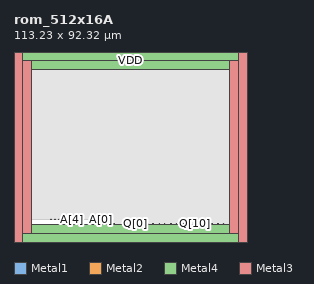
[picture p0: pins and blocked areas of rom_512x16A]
MACRO rom_512x16A
  CLASS RING ;
  FOREIGN rom_512x16A 0 0 ;
  ORIGIN 0 0 ;
  SIZE 113.23 BY 92.32 ;
  SYMMETRY X Y R90 ;
  PIN A[0]
    DIRECTION INPUT ;
    USE SIGNAL ;
    AntennaGateArea  0.039 ;
    PORT
      LAYER Metal1 ;
        RECT 42.27 10.76 42.6 11.09 ;
      LAYER Metal2 ;
        RECT 42.27 10.76 42.6 11.09 ;
      LAYER Metal4 ;
        RECT 42.27 10.76 42.6 11.09 ;
      LAYER Metal3 ;
        RECT 42.27 10.76 42.6 11.09 ;
      END
    END A[0]
  PIN A[1]
    DIRECTION INPUT ;
    USE SIGNAL ;
    AntennaGateArea  0.039 ;
    PORT
      LAYER Metal1 ;
        RECT 40.22 10.76 40.55 11.09 ;
      LAYER Metal2 ;
        RECT 40.22 10.76 40.55 11.09 ;
      LAYER Metal4 ;
        RECT 40.22 10.76 40.55 11.09 ;
      LAYER Metal3 ;
        RECT 40.22 10.76 40.55 11.09 ;
      END
    END A[1]
  PIN A[2]
    DIRECTION INPUT ;
    AntennaGateArea  0.039 ;
    USE SIGNAL ;
    PORT
      LAYER Metal1 ;
        RECT 38.17 10.76 38.5 11.09 ;
      LAYER Metal2 ;
        RECT 38.17 10.76 38.5 11.09 ;
      LAYER Metal4 ;
        RECT 38.17 10.76 38.5 11.09 ;
      LAYER Metal3 ;
        RECT 38.17 10.76 38.5 11.09 ;
      END
    END A[2]
  PIN A[3]
    DIRECTION INPUT ;
    USE SIGNAL ;
    AntennaGateArea  0.039 ;
    PORT
      LAYER Metal1 ;
        RECT 29.97 10.76 30.3 11.09 ;
      LAYER Metal2 ;
        RECT 29.97 10.76 30.3 11.09 ;
      LAYER Metal4 ;
        RECT 29.97 10.76 30.3 11.09 ;
      LAYER Metal3 ;
        RECT 29.97 10.76 30.3 11.09 ;
      END
    END A[3]
  PIN A[4]
    DIRECTION INPUT ;
    USE SIGNAL ;
    AntennaGateArea  0.039 ;
    PORT
      LAYER Metal1 ;
        RECT 27.92 10.76 28. 11.09 ;
      LAYER Metal2 ;
        RECT 27.92 10.76 28. 11.09 ;
      LAYER Metal4 ;
        RECT 27.92 10.76 28. 11.09 ;
      LAYER Metal3 ;
        RECT 27.92 10.76 28. 11.09 ;
      END
    END A[4]
  PIN A[5]
    DIRECTION INPUT ;
    USE SIGNAL ;
    AntennaGateArea  0.039 ;
    PORT
      LAYER Metal1 ;
        RECT 25.87 10.76 26.2 11.09 ;
      LAYER Metal2 ;
        RECT 25.87 10.76 26.2 11.09 ;
      LAYER Metal4 ;
        RECT 25.87 10.76 26.2 11.09 ;
      LAYER Metal3 ;
        RECT 25.87 10.76 26.2 11.09 ;
      END
    END A[5]
  PIN A[6]
    DIRECTION INPUT ;
    USE SIGNAL ;
    AntennaGateArea  0.039 ;
    PORT
      LAYER Metal1 ;
        RECT 21.77 10.76 22.1 11.09 ;
      LAYER Metal2 ;
        RECT 21.77 10.76 22.1 11.09 ;
      LAYER Metal4 ;
        RECT 21.77 10.76 22.1 11.09 ;
      LAYER Metal3 ;
        RECT 21.77 10.76 22.1 11.09 ;
      END
    END A[6]
  PIN A[7]
    DIRECTION INPUT ;
    USE SIGNAL ;
    AntennaGateArea  0.039 ;
    PORT
      LAYER Metal1 ;
        RECT 19.72 10.76 20.05 11.09 ;
      LAYER Metal2 ;
        RECT 19.72 10.76 20.05 11.09 ;
      LAYER Metal4 ;
        RECT 19.72 10.76 20.05 11.09 ;
      LAYER Metal3 ;
        RECT 19.72 10.76 20.05 11.09 ;
      END
    END A[7]
  PIN A[8]
    DIRECTION INPUT ;
    USE SIGNAL ;
    AntennaGateArea  0.039 ;
    PORT
      LAYER Metal1 ;
        RECT 17.67 10.76 18 11.09 ;
      LAYER Metal2 ;
        RECT 17.67 10.76 18 11.09 ;
      LAYER Metal4 ;
        RECT 17.67 10.76 18 11.09 ;
      LAYER Metal3 ;
        RECT 17.67 10.76 18 11.09 ;
      END
    END A[8]
  PIN CEN
    DIRECTION INPUT ;
    USE SIGNAL ;
    AntennaGateArea  0.039 ;
    PORT
      LAYER Metal1 ;
        RECT 46.955 8.6 47.285 8.93 ;
      LAYER Metal2 ;
        RECT 46.955 8.6 47.285 8.93 ;
      LAYER Metal4 ;
        RECT 46.955 8.6 47.285 8.93 ;
      LAYER Metal3 ;
        RECT 46.955 8.6 47.285 8.93 ;
      END
    END CEN
  PIN CLK
    DIRECTION INPUT ;
    USE CLOCK ;
    AntennaGateArea  0.039 ;
    PORT
      LAYER Metal1 ;
        RECT 48.53 8.6 48.86 8.93 ;
      LAYER Metal2 ;
        RECT 48.53 8.6 48.86 8.93 ;
      LAYER Metal4 ;
        RECT 48.53 8.6 48.86 8.93 ;
      LAYER Metal3 ;
        RECT 48.53 8.6 48.86 8.93 ;
      END
    END CLK
  PIN Q[0]
    DIRECTION OUTPUT ;
    USE SIGNAL ;
    ANTENNADIFFAREA 1.7285  LAYER Metal1 ;
    PORT
      LAYER Metal1 ;
        RECT 59.02 8.6 59.35 8.93 ;
      LAYER Metal2 ;
        RECT 59.02 8.6 59.35 8.93 ;
      LAYER Metal4 ;
        RECT 59.02 8.6 59.35 8.93 ;
      LAYER Metal3 ;
        RECT 59.02 8.6 59.35 8.93 ;
      END
    END Q[0]
  PIN Q[10]
    DIRECTION OUTPUT ;
    USE SIGNAL ;
    ANTENNADIFFAREA 1.7285  LAYER Metal1 ;
    PORT
      LAYER Metal1 ;
        RECT 87.62 8.6 87.95 8.93 ;
      LAYER Metal2 ;
        RECT 87.62 8.6 87.95 8.93 ;
      LAYER Metal4 ;
        RECT 87.62 8.6 87.95 8.93 ;
      LAYER Metal3 ;
        RECT 87.62 8.6 87.95 8.93 ;
      END
    END Q[10]
  PIN Q[11]
    DIRECTION OUTPUT ;
    USE SIGNAL ;
    ANTENNADIFFAREA 1.7285  LAYER Metal1 ;
    PORT
      LAYER Metal1 ;
        RECT 90.18 8.6 90.51 8.93 ;
      LAYER Metal2 ;
        RECT 90.18 8.6 90.51 8.93 ;
      LAYER Metal4 ;
        RECT 90.18 8.6 90.51 8.93 ;
      LAYER Metal3 ;
        RECT 90.18 8.6 90.51 8.93 ;
      END
    END Q[11]
  PIN Q[12]
    DIRECTION OUTPUT ;
    USE SIGNAL ;
    ANTENNADIFFAREA 1.7285  LAYER Metal1 ;
    PORT
      LAYER Metal1 ;
        RECT 93.34 8.6 93.67 8.93 ;
      LAYER Metal2 ;
        RECT 93.34 8.6 93.67 8.93 ;
      LAYER Metal4 ;
        RECT 93.34 8.6 93.67 8.93 ;
      LAYER Metal3 ;
        RECT 93.34 8.6 93.67 8.93 ;
      END
    END Q[12]
  PIN Q[13]
    DIRECTION OUTPUT ;
    USE SIGNAL ;
    ANTENNADIFFAREA 1.7285  LAYER Metal1 ;
    PORT
      LAYER Metal1 ;
        RECT 95.90 8.6 96.23 8.93 ;
      LAYER Metal2 ;
        RECT 95.90 8.6 96.23 8.93 ;
      LAYER Metal4 ;
        RECT 95.90 8.6 96.23 8.93 ;
      LAYER Metal3 ;
        RECT 95.90 8.6 96.23 8.93 ;
      END
    END Q[13]
  PIN Q[14]
    DIRECTION OUTPUT ;
    USE SIGNAL ;
    ANTENNADIFFAREA 1.7285  LAYER Metal1 ;
    PORT
      LAYER Metal1 ;
        RECT 99.06 8.6 99.39 8.93 ;
      LAYER Metal2 ;
        RECT 99.06 8.6 99.39 8.93 ;
      LAYER Metal4 ;
        RECT 99.06 8.6 99.39 8.93 ;
      LAYER Metal3 ;
        RECT 99.06 8.6 99.39 8.93 ;
      END
    END Q[14]
  PIN Q[15]
    DIRECTION OUTPUT ;
    USE SIGNAL ;
    ANTENNADIFFAREA 1.7285  LAYER Metal1 ;
    PORT
      LAYER Metal1 ;
        RECT 101.62 8.6 101.95 8.93 ;
      LAYER Metal2 ;
        RECT 101.62 8.6 101.95 8.93 ;
      LAYER Metal4 ;
        RECT 101.62 8.6 101.95 8.93 ;
      LAYER Metal3 ;
        RECT 101.62 8.6 101.95 8.93 ;
      END
    END Q[15]
  PIN Q[1]
    DIRECTION OUTPUT ;
    USE SIGNAL ;
    ANTENNADIFFAREA 1.7285  LAYER Metal1 ;
    PORT
      LAYER Metal1 ;
        RECT 61.58 8.6 61.91 8.93 ;
      LAYER Metal2 ;
        RECT 61.58 8.6 61.91 8.93 ;
      LAYER Metal4 ;
        RECT 61.58 8.6 61.91 8.93 ;
      LAYER Metal3 ;
        RECT 61.58 8.6 61.91 8.93 ;
      END
    END Q[1]
  PIN Q[2]
    DIRECTION OUTPUT ;
    USE SIGNAL ;
    ANTENNADIFFAREA 1.7285  LAYER Metal1 ;
    PORT
      LAYER Metal1 ;
        RECT 64.74 8.6 65.07 8.93 ;
      LAYER Metal2 ;
        RECT 64.74 8.6 65.07 8.93 ;
      LAYER Metal4 ;
        RECT 64.74 8.6 65.07 8.93 ;
      LAYER Metal3 ;
        RECT 64.74 8.6 65.07 8.93 ;
      END
    END Q[2]
  PIN Q[3]
    DIRECTION OUTPUT ;
    USE SIGNAL ;
    ANTENNADIFFAREA 1.7285  LAYER Metal1 ;
    PORT
      LAYER Metal1 ;
        RECT 67.30 8.6 67.63 8.93 ;
      LAYER Metal2 ;
        RECT 67.30 8.6 67.63 8.93 ;
      LAYER Metal4 ;
        RECT 67.30 8.6 67.63 8.93 ;
      LAYER Metal3 ;
        RECT 67.30 8.6 67.63 8.93 ;
      END
    END Q[3]
  PIN Q[4]
    DIRECTION OUTPUT ;
    USE SIGNAL ;
    ANTENNADIFFAREA 1.7285  LAYER Metal1 ;
    PORT
      LAYER Metal1 ;
        RECT 70.46 8.6 70.79 8.93 ;
      LAYER Metal2 ;
        RECT 70.46 8.6 70.79 8.93 ;
      LAYER Metal4 ;
        RECT 70.46 8.6 70.79 8.93 ;
      LAYER Metal3 ;
        RECT 70.46 8.6 70.79 8.93 ;
      END
    END Q[4]
  PIN Q[5]
    DIRECTION OUTPUT ;
    USE SIGNAL ;
    ANTENNADIFFAREA 1.7285  LAYER Metal1 ;
    PORT
      LAYER Metal1 ;
        RECT 73.02 8.6 73.35 8.93 ;
      LAYER Metal2 ;
        RECT 73.02 8.6 73.35 8.93 ;
      LAYER Metal4 ;
        RECT 73.02 8.6 73.35 8.93 ;
      LAYER Metal3 ;
        RECT 73.02 8.6 73.35 8.93 ;
      END
    END Q[5]
  PIN Q[6]
    DIRECTION OUTPUT ;
    USE SIGNAL ;
    ANTENNADIFFAREA 1.7285  LAYER Metal1 ;
    PORT
      LAYER Metal1 ;
        RECT 76.18 8.6 76.51 8.93 ;
      LAYER Metal2 ;
        RECT 76.18 8.6 76.51 8.93 ;
      LAYER Metal4 ;
        RECT 76.18 8.6 76.51 8.93 ;
      LAYER Metal3 ;
        RECT 76.18 8.6 76.51 8.93 ;
      END
    END Q[6]
  PIN Q[7]
    DIRECTION OUTPUT ;
    USE SIGNAL ;
    ANTENNADIFFAREA 1.7285  LAYER Metal1 ;
    PORT
      LAYER Metal1 ;
        RECT 78.74 8.6 79.07 8.93 ;
      LAYER Metal2 ;
        RECT 78.74 8.6 79.07 8.93 ;
      LAYER Metal4 ;
        RECT 78.74 8.6 79.07 8.93 ;
      LAYER Metal3 ;
        RECT 78.74 8.6 79.07 8.93 ;
      END
    END Q[7]
  PIN Q[8]
    DIRECTION OUTPUT ;
    USE SIGNAL ;
    ANTENNADIFFAREA 1.7285  LAYER Metal1 ;
    PORT
      LAYER Metal1 ;
        RECT 81.90 8.6 82.23 8.93 ;
      LAYER Metal2 ;
        RECT 81.90 8.6 82.23 8.93 ;
      LAYER Metal4 ;
        RECT 81.90 8.6 82.23 8.93 ;
      LAYER Metal3 ;
        RECT 81.90 8.6 82.23 8.93 ;
      END
    END Q[8]
  PIN Q[9]
    DIRECTION OUTPUT ;
    USE SIGNAL ;
    ANTENNADIFFAREA 1.7285  LAYER Metal1 ;
    PORT
      LAYER Metal1 ;
        RECT 84.46 8.6 84.79 8.93 ;
      LAYER Metal2 ;
        RECT 84.46 8.6 84.79 8.93 ;
      LAYER Metal4 ;
        RECT 84.46 8.6 84.79 8.93 ;
      LAYER Metal3 ;
        RECT 84.46 8.6 84.79 8.93 ;
      END
    END Q[9]
  PIN VDD
    DIRECTION INOUT ;
    USE POWER ;
    SHAPE RING ;
    PORT
      LAYER Metal4 ;
        RECT 113.23 88.32 0 92.32 ;
      LAYER Metal4 ;
        RECT 0 0 113.23 4 ;
      LAYER Metal3 ;
        RECT 109.23 0 113.23 92.32 ;
      LAYER Metal3 ;
        RECT 0 92.32 4 0 ;
      END
    END VDD
  PIN VSS
    DIRECTION INOUT ;
    USE GROUND ;
    SHAPE RING ;
    PORT
      LAYER Metal4 ;
        RECT 108.93 84.02 4.3 88.02 ;
      LAYER Metal4 ;
        RECT 4.3 4.3 108.93 8.3 ;
      LAYER Metal3 ;
        RECT 104.93 4.3 108.93 88.02 ;
      LAYER Metal3 ;
        RECT 4.3 88.02 8.3 4.3 ;
      END
    END VSS
  OBS
    LAYER OVERLAP ;
POLYGON 8.6 10.76 45.995 10.76 45.995 8.6 104.63 8.6 104.63 83.72 
8.6 83.72 ; 
    LAYER Via1 ;
POLYGON 8.6 10.76 45.995 10.76 45.995 8.6 104.63 8.6 104.63 83.72 
8.6 83.72 ; 
    LAYER Via2 ;
POLYGON 8.6 10.76 45.995 10.76 45.995 8.6 104.63 8.6 104.63 83.72 
8.6 83.72 ; 
    LAYER Via3 ;
POLYGON 8.6 10.76 45.995 10.76 45.995 8.6 104.63 8.6 104.63 83.72 
8.6 83.72 ; 
    LAYER Via4 ;
POLYGON 8.6 10.76 45.995 10.76 45.995 8.6 104.63 8.6 104.63 83.72 
8.6 83.72 ; 
    LAYER Metal1 ;
POLYGON 8.6 83.72 8.6 10.76 17.58 10.76 17.58 11.18 18.09 11.18 
18.09 10.76 19.63 10.76 19.63 11.18 20.14 11.18 20.14 10.76 21.68 10.76 
21.68 11.18 22.19 11.18 22.19 10.76 25.78 10.76 25.78 11.18 26.29 11.18 
26.29 10.76 27.83 10.76 27.83 11.18 28.34 11.18 28.34 10.76 29.88 10.76 
29.88 11.18 30.39 11.18 30.39 10.76 38.08 10.76 38.08 11.18 38.59 11.18 
38.59 10.76 40.13 10.76 40.13 11.18 40.64 11.18 40.64 10.76 42.18 10.76 
42.18 11.18 42.69 11.18 42.69 10.76 45.995 10.76 45.995 8.6 46.865 8.6 
46.865 9.02 47.3 9.02 47.3 8.6 48.44 8.6 48.44 9.02 
48.95 9.02 48.95 8.6 58.93 8.6 58.93 9.02 59.44 9.02 
59.44 8.6 61.49 8.6 61.49 9.02 62.00 9.02 62.00 8.6 
64.65 8.6 64.65 9.02 65.16 9.02 65.16 8.6 67.21 8.6 
67.21 9.02 67.72 9.02 67.72 8.6 70.37 8.6 70.37 9.02 
70.88 9.02 70.88 8.6 72.93 8.6 72.93 9.02 73.44 9.02 
73.44 8.6 76.09 8.6 76.09 9.02 76.60 9.02 76.60 8.6 
78.65 8.6 78.65 9.02 79.16 9.02 79.16 8.6 81.81 8.6 
81.81 9.02 82.32 9.02 82.32 8.6 84.37 8.6 84.37 9.02 
84.88 9.02 84.88 8.6 87.53 8.6 87.53 9.02 88.04 9.02 
88.04 8.6 90.09 8.6 90.09 9.02 90.60 9.02 90.60 8.6 
93.25 8.6 93.25 9.02 93.76 9.02 93.76 8.6 95.81 8.6 
95.81 9.02 96.32 9.02 96.32 8.6 98.97 8.6 98.97 9.02 
99.48 9.02 99.48 8.6 101.53 8.6 101.53 9.02 102.04 9.02 
102.04 8.6 104.63 8.6 104.63 83.72 ; 
    LAYER Metal2 ;
POLYGON 8.6 83.72 8.6 10.76 17.565 10.76 17.565 11.195 18.105 11.195 
18.105 10.76 19.615 10.76 19.615 11.195 20.155 11.195 20.155 10.76 21.665 10.76 
21.665 11.195 22.205 11.195 22.205 10.76 25.765 10.76 25.765 11.195 26.305 11.195 
26.305 10.76 27.815 10.76 27.815 11.195 28.355 11.195 28.355 10.76 29.865 10.76 
29.865 11.195 30.405 11.195 30.405 10.76 38.065 10.76 38.065 11.195 38.605 11.195 
38.605 10.76 40.115 10.76 40.115 11.195 40.655 11.195 40.655 10.76 42.165 10.76 
42.165 11.195 42.705 11.195 42.705 10.76 45.995 10.76 45.995 8.6 46.85 8.6 
46.85 9.035 47.39 9.035 47.39 8.6 48.42 8.6 48.42 9.035 48.96 9.035 
48.96 8.6 58.92 8.6 58.92 9.035 59.46 9.035 59.46 8.6 
61.48 8.6 61.48 9.035 62.02 9.035 62.02 8.6 64.64 8.6 
64.64 9.035 65.18 9.035 65.18 8.6 67.20 8.6 67.20 9.035 
67.74 9.035 67.74 8.6 70.36 8.6 70.36 9.035 70.90 9.035 
70.90 8.6 72.92 8.6 72.92 9.035 73.46 9.035 73.46 8.6 
76.08 8.6 76.08 9.035 76.62 9.035 76.62 8.6 78.64 8.6 
78.64 9.035 79.18 9.035 79.18 8.6 81.80 8.6 81.80 9.035 
82.34 9.035 82.34 8.6 84.36 8.6 84.36 9.035 84.90 9.035 
84.90 8.6 87.52 8.6 87.52 9.035 88.06 9.035 88.06 8.6 
90.08 8.6 90.08 9.035 90.62 9.035 90.62 8.6 93.24 8.6 
93.24 9.035 93.78 9.035 93.78 8.6 95.80 8.6 95.80 9.035 
96.34 9.035 96.34 8.6 98.96 8.6 98.96 9.035 99.50 9.035 
99.50 8.6 101.52 8.6 101.52 9.035 102.06 9.035 102.06 8.6 
104.63 8.6 104.63 83.72 ; 
    LAYER Metal4 ;
POLYGON 8.6 83.72 8.6 10.76 17.565 10.76 17.565 11.195 18.105 11.195 
18.105 10.76 19.615 10.76 19.615 11.195 20.155 11.195 20.155 10.76 21.665 10.76 
21.665 11.195 22.205 11.195 22.205 10.76 25.765 10.76 25.765 11.195 26.305 11.195 
26.305 10.76 27.815 10.76 27.815 11.195 28.355 11.195 28.355 10.76 29.865 10.76 
29.865 11.195 30.405 11.195 30.405 10.76 38.065 10.76 38.065 11.195 38.605 11.195 
38.605 10.76 40.115 10.76 40.115 11.195 40.655 11.195 40.655 10.76 42.165 10.76 
42.165 11.195 42.705 11.195 42.705 10.76 45.995 10.76 45.995 8.6 46.85 8.6 
46.85 9.035 47.39 9.035 47.39 8.6 48.42 8.6 48.42 9.035 48.96 9.035 
48.96 8.6 58.92 8.6 58.92 9.035 59.46 9.035 59.46 8.6 
61.48 8.6 61.48 9.035 62.02 9.035 62.02 8.6 64.64 8.6 
64.64 9.035 65.18 9.035 65.18 8.6 67.20 8.6 67.20 9.035 
67.74 9.035 67.74 8.6 70.36 8.6 70.36 9.035 70.90 9.035 
70.90 8.6 72.92 8.6 72.92 9.035 73.46 9.035 73.46 8.6 
76.08 8.6 76.08 9.035 76.62 9.035 76.62 8.6 78.64 8.6 
78.64 9.035 79.18 9.035 79.18 8.6 81.80 8.6 81.80 9.035 
82.34 9.035 82.34 8.6 84.36 8.6 84.36 9.035 84.90 9.035 
84.90 8.6 87.52 8.6 87.52 9.035 88.06 9.035 88.06 8.6 
90.08 8.6 90.08 9.035 90.62 9.035 90.62 8.6 93.24 8.6 
93.24 9.035 93.78 9.035 93.78 8.6 95.80 8.6 95.80 9.035 
96.34 9.035 96.34 8.6 98.96 8.6 98.96 9.035 99.50 9.035 
99.50 8.6 101.52 8.6 101.52 9.035 102.06 9.035 102.06 8.6 
104.63 8.6 104.63 83.72 ; 
    LAYER Metal3 ;
POLYGON 8.6 83.72 8.6 10.76 17.565 10.76 17.565 11.195 18.105 11.195 
18.105 10.76 19.615 10.76 19.615 11.195 20.155 11.195 20.155 10.76 21.665 10.76 
21.665 11.195 22.205 11.195 22.205 10.76 25.765 10.76 25.765 11.195 26.305 11.195 
26.305 10.76 27.815 10.76 27.815 11.195 28.355 11.195 28.355 10.76 29.865 10.76 
29.865 11.195 30.405 11.195 30.405 10.76 38.065 10.76 38.065 11.195 38.605 11.195 
38.605 10.76 40.115 10.76 40.115 11.195 40.655 11.195 40.655 10.76 42.165 10.76 
42.165 11.195 42.705 11.195 42.705 10.76 45.995 10.76 45.995 8.6 46.85 8.6 
46.85 9.035 47.39 9.035 47.39 8.6 48.42 8.6 48.42 9.035 48.96 9.035 
48.96 8.6 58.92 8.6 58.92 9.035 59.46 9.035 59.46 8.6 
61.48 8.6 61.48 9.035 62.02 9.035 62.02 8.6 64.64 8.6 
64.64 9.035 65.18 9.035 65.18 8.6 67.20 8.6 67.20 9.035 
67.74 9.035 67.74 8.6 70.36 8.6 70.36 9.035 70.90 9.035 
70.90 8.6 72.92 8.6 72.92 9.035 73.46 9.035 73.46 8.6 
76.08 8.6 76.08 9.035 76.62 9.035 76.62 8.6 78.64 8.6 
78.64 9.035 79.18 9.035 79.18 8.6 81.80 8.6 81.80 9.035 
82.34 9.035 82.34 8.6 84.36 8.6 84.36 9.035 84.90 9.035 
84.90 8.6 87.52 8.6 87.52 9.035 88.06 9.035 88.06 8.6 
90.08 8.6 90.08 9.035 90.62 9.035 90.62 8.6 93.24 8.6 
93.24 9.035 93.78 9.035 93.78 8.6 95.80 8.6 95.80 9.035 
96.34 9.035 96.34 8.6 98.96 8.6 98.96 9.035 99.50 9.035 
99.50 8.6 101.52 8.6 101.52 9.035 102.06 9.035 102.06 8.6 
104.63 8.6 104.63 83.72 ; 
    LAYER Metal4 ;
        RECT 104.63 10.54 113.23 11.24 ;
    LAYER Metal4 ;
        RECT 104.63 15.17 113.23 15.87 ;
    LAYER Metal4 ;
        RECT 104.63 16.30 113.23 17.00 ;
    LAYER Metal4 ;
        RECT 104.63 17.61 113.23 17.96 ;
    LAYER Metal4 ;
        RECT 104.63 20.13 113.23 21.37 ;
    LAYER Metal4 ;
        RECT 104.63 22.66 113.23 23.96 ;
    LAYER Metal4 ;
        RECT 104.63 25.25 113.23 25.87 ;
    LAYER Metal4 ;
        RECT 104.63 26.72 113.23 27.27 ;
    LAYER Metal4 ;
        RECT 104.63 28.565 113.23 28.915 ;
    LAYER Metal4 ;
        RECT 104.63 33.295 113.23 33.85 ;
    LAYER Metal4 ;
        RECT 104.63 36.155 113.23 37.055 ;
    LAYER Metal4 ;
        RECT 104.63 40.47 113.23 40.82 ;
    LAYER Metal4 ;
        RECT 104.63 42.06 113.23 42.96 ;
    LAYER Metal4 ;
        RECT 104.63 45.26 113.23 45.82 ;
    LAYER Metal4 ;
        RECT 104.63 50.02 113.23 50.37 ;
    LAYER Metal4 ;
        RECT 104.63 51.42 113.23 51.77 ;
    LAYER Metal4 ;
        RECT 104.63 54.83 113.23 56.03 ;
    LAYER Metal4 ;
        RECT 104.63 56.805 113.23 58.005 ;
    LAYER Metal4 ;
        RECT 8.6 12.44 0 12.79 ;
    LAYER Metal4 ;
        RECT 8.6 16.47 0 16.87 ;
    LAYER Metal4 ;
        RECT 8.6 17.52 0 17.87 ;
    LAYER Metal4 ;
        RECT 8.6 20.185 0 20.805 ;
    LAYER Metal4 ;
        RECT 8.6 21.98 0 23.28 ;
    LAYER Metal4 ;
        RECT 8.6 25.25 0 25.87 ;
    LAYER Metal4 ;
        RECT 8.6 26.72 0 27.27 ;
    LAYER Metal4 ;
        RECT 8.6 28.565 0 28.915 ;
    LAYER Metal4 ;
        RECT 8.6 33.295 0 33.85 ;
    LAYER Metal4 ;
        RECT 8.6 36.155 0 37.055 ;
    LAYER Metal4 ;
        RECT 8.6 40.44 0 40.79 ;
    LAYER Metal4 ;
        RECT 8.6 42.06 0 42.96 ;
    LAYER Metal4 ;
        RECT 8.6 45.26 0 45.82 ;
    LAYER Metal4 ;
        RECT 8.6 50.02 0 50.37 ;
    LAYER Metal4 ;
        RECT 8.6 54.83 0 56.03 ;
    LAYER Metal4 ;
        RECT 8.6 56.805 0 58.005 ;
    LAYER Metal4 ;
        RECT 8.6 62.31 0 62.66 ;
    LAYER Metal4 ;
        RECT 8.6 82.1 0 82.5 ;
    LAYER Metal4 ;
        RECT 104.63 9.14 108.93 9.84 ;
    LAYER Metal4 ;
        RECT 104.63 11.84 108.93 12.54 ;
    LAYER Metal4 ;
        RECT 104.63 18.755 108.93 19.3 ;
    LAYER Metal4 ;
        RECT 104.63 24.41 108.93 24.81 ;
    LAYER Metal4 ;
        RECT 104.63 32.15 108.93 32.705 ;
    LAYER Metal4 ;
        RECT 104.63 34.08 108.93 34.43 ;
    LAYER Metal4 ;
        RECT 104.63 38.56 108.93 38.91 ;
    LAYER Metal4 ;
        RECT 104.63 41.05 108.93 41.60 ;
    LAYER Metal4 ;
        RECT 104.63 44.68 108.93 45.03 ;
    LAYER Metal4 ;
        RECT 104.63 46.38 108.93 46.93 ;
    LAYER Metal4 ;
        RECT 104.63 53.84 108.93 54.60 ;
    LAYER Metal4 ;
        RECT 104.63 59.095 108.93 60.095 ;
    LAYER Metal4 ;
        RECT 104.63 61.36 108.93 62.36 ;
    LAYER Metal4 ;
        RECT 104.63 62.61 108.93 63.61 ;
    LAYER Metal4 ;
        RECT 104.63 63.86 108.93 64.86 ;
    LAYER Metal4 ;
        RECT 104.63 65.11 108.93 66.11 ;
    LAYER Metal4 ;
        RECT 104.63 66.36 108.93 67.36 ;
    LAYER Metal4 ;
        RECT 104.63 67.61 108.93 68.61 ;
    LAYER Metal4 ;
        RECT 104.63 68.86 108.93 69.86 ;
    LAYER Metal4 ;
        RECT 104.63 70.11 108.93 71.11 ;
    LAYER Metal4 ;
        RECT 104.63 71.36 108.93 72.36 ;
    LAYER Metal4 ;
        RECT 104.63 72.61 108.93 73.61 ;
    LAYER Metal4 ;
        RECT 104.63 73.86 108.93 74.86 ;
    LAYER Metal4 ;
        RECT 104.63 75.11 108.93 76.11 ;
    LAYER Metal4 ;
        RECT 104.63 76.36 108.93 77.36 ;
    LAYER Metal4 ;
        RECT 104.63 77.61 108.93 78.61 ;
    LAYER Metal4 ;
        RECT 104.63 78.86 108.93 79.86 ;
    LAYER Metal4 ;
        RECT 104.63 80.11 108.93 81.11 ;
    LAYER Metal4 ;
        RECT 104.63 81.35 108.93 82.85 ;
    LAYER Metal4 ;
        RECT 8.6 13.90 4.3 14.30 ;
    LAYER Metal4 ;
        RECT 8.6 15.24 4.3 16.24 ;
    LAYER Metal4 ;
        RECT 8.6 18.10 4.3 18.72 ;
    LAYER Metal4 ;
        RECT 8.6 24.41 4.3 24.81 ;
    LAYER Metal4 ;
        RECT 8.6 32.15 4.3 32.705 ;
    LAYER Metal4 ;
        RECT 8.6 34.1 4.3 34.45 ;
    LAYER Metal4 ;
        RECT 8.6 38.56 4.3 38.91 ;
    LAYER Metal4 ;
        RECT 8.6 41.05 4.3 41.60 ;
    LAYER Metal4 ;
        RECT 8.6 44.66 4.3 45.01 ;
    LAYER Metal4 ;
        RECT 8.6 46.41 4.3 46.91 ;
    LAYER Metal4 ;
        RECT 8.6 53.90 4.3 54.60 ;
    LAYER Metal4 ;
        RECT 8.6 61.06 4.3 61.41 ;
    LAYER Metal4 ;
        RECT 8.6 63.56 4.3 63.91 ;
    LAYER Metal4 ;
        RECT 8.6 64.81 4.3 65.16 ;
    LAYER Metal4 ;
        RECT 8.6 66.06 4.3 66.41 ;
    LAYER Metal4 ;
        RECT 8.6 67.31 4.3 67.66 ;
    LAYER Metal4 ;
        RECT 8.6 68.56 4.3 68.91 ;
    LAYER Metal4 ;
        RECT 8.6 69.81 4.3 70.16 ;
    LAYER Metal4 ;
        RECT 8.6 71.06 4.3 71.41 ;
    LAYER Metal4 ;
        RECT 8.6 72.31 4.3 72.66 ;
    LAYER Metal4 ;
        RECT 8.6 73.56 4.3 73.91 ;
    LAYER Metal4 ;
        RECT 8.6 74.81 4.3 75.16 ;
    LAYER Metal4 ;
        RECT 8.6 76.06 4.3 76.41 ;
    LAYER Metal4 ;
        RECT 8.6 77.31 4.3 77.66 ;
    LAYER Metal4 ;
        RECT 8.6 78.56 4.3 78.91 ;
    LAYER Metal4 ;
        RECT 8.6 79.81 4.3 80.16 ;
    LAYER Metal4 ;
        RECT 8.6 81.06 4.3 81.41 ;
    END
  END rom_512x16A
END LIBRARY

